# Generated by FakeRAM 2.0 (routing-friendly)
VERSION 5.7 ;
BUSBITCHARS "[]" ;
PROPERTYDEFINITIONS
  MACRO width INTEGER ;
  MACRO depth INTEGER ;
  MACRO banks INTEGER ;
END PROPERTYDEFINITIONS
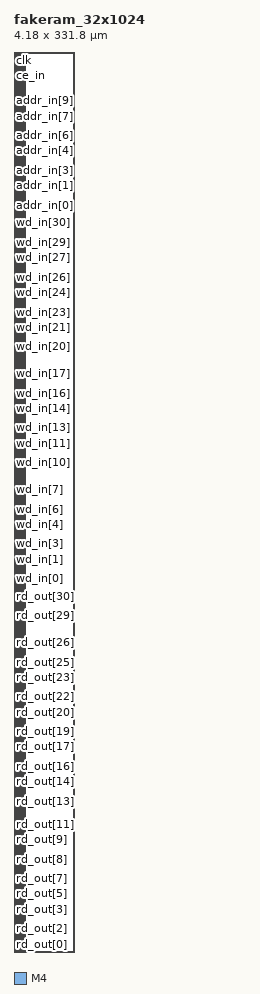
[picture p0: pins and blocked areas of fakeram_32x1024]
MACRO fakeram_32x1024
  PROPERTY width 32 ;
  PROPERTY depth 1024 ;
  PROPERTY banks 1 ;
  FOREIGN fakeram_32x1024 0 0 ;
  SYMMETRY X Y R90 ;
  SIZE 4.180 BY 331.800 ;
  CLASS BLOCK ;
  PIN rd_out[0]
    DIRECTION OUTPUT ;
    USE SIGNAL ;
    PORT
      LAYER M4 ;
      RECT 1.000 0.048 3.000 0.072 ;
    END
    PORT
      LAYER M4 ;
      RECT 1.000 0.036 4.000 0.084 ;
    END
  END rd_out[0]
  PIN rd_out[1]
    DIRECTION OUTPUT ;
    USE SIGNAL ;
    PORT
      LAYER M4 ;
      RECT 1.000 4.320 3.000 4.344 ;
    END
    PORT
      LAYER M4 ;
      RECT 1.000 4.308 4.000 4.356 ;
    END
  END rd_out[1]
  PIN rd_out[2]
    DIRECTION OUTPUT ;
    USE SIGNAL ;
    PORT
      LAYER M4 ;
      RECT 1.000 8.592 3.000 8.616 ;
    END
    PORT
      LAYER M4 ;
      RECT 1.000 8.580 4.000 8.628 ;
    END
  END rd_out[2]
  PIN rd_out[3]
    DIRECTION OUTPUT ;
    USE SIGNAL ;
    PORT
      LAYER M4 ;
      RECT 1.000 12.864 3.000 12.888 ;
    END
    PORT
      LAYER M4 ;
      RECT 1.000 12.852 4.000 12.900 ;
    END
  END rd_out[3]
  PIN rd_out[4]
    DIRECTION OUTPUT ;
    USE SIGNAL ;
    PORT
      LAYER M4 ;
      RECT 1.000 17.136 3.000 17.160 ;
    END
    PORT
      LAYER M4 ;
      RECT 1.000 17.124 4.000 17.172 ;
    END
  END rd_out[4]
  PIN rd_out[5]
    DIRECTION OUTPUT ;
    USE SIGNAL ;
    PORT
      LAYER M4 ;
      RECT 1.000 21.408 3.000 21.432 ;
    END
    PORT
      LAYER M4 ;
      RECT 1.000 21.396 4.000 21.444 ;
    END
  END rd_out[5]
  PIN rd_out[6]
    DIRECTION OUTPUT ;
    USE SIGNAL ;
    PORT
      LAYER M4 ;
      RECT 1.000 25.680 3.000 25.704 ;
    END
    PORT
      LAYER M4 ;
      RECT 1.000 25.668 4.000 25.716 ;
    END
  END rd_out[6]
  PIN rd_out[7]
    DIRECTION OUTPUT ;
    USE SIGNAL ;
    PORT
      LAYER M4 ;
      RECT 1.000 29.952 3.000 29.976 ;
    END
    PORT
      LAYER M4 ;
      RECT 1.000 29.940 4.000 29.988 ;
    END
  END rd_out[7]
  PIN rd_out[8]
    DIRECTION OUTPUT ;
    USE SIGNAL ;
    PORT
      LAYER M4 ;
      RECT 1.000 34.224 3.000 34.248 ;
    END
    PORT
      LAYER M4 ;
      RECT 1.000 34.212 4.000 34.260 ;
    END
  END rd_out[8]
  PIN rd_out[9]
    DIRECTION OUTPUT ;
    USE SIGNAL ;
    PORT
      LAYER M4 ;
      RECT 1.000 38.496 3.000 38.520 ;
    END
    PORT
      LAYER M4 ;
      RECT 1.000 38.484 4.000 38.532 ;
    END
  END rd_out[9]
  PIN rd_out[10]
    DIRECTION OUTPUT ;
    USE SIGNAL ;
    PORT
      LAYER M4 ;
      RECT 1.000 42.768 3.000 42.792 ;
    END
    PORT
      LAYER M4 ;
      RECT 1.000 42.756 4.000 42.804 ;
    END
  END rd_out[10]
  PIN rd_out[11]
    DIRECTION OUTPUT ;
    USE SIGNAL ;
    PORT
      LAYER M4 ;
      RECT 1.000 47.040 3.000 47.064 ;
    END
    PORT
      LAYER M4 ;
      RECT 1.000 47.028 4.000 47.076 ;
    END
  END rd_out[11]
  PIN rd_out[12]
    DIRECTION OUTPUT ;
    USE SIGNAL ;
    PORT
      LAYER M4 ;
      RECT 1.000 51.312 3.000 51.336 ;
    END
    PORT
      LAYER M4 ;
      RECT 1.000 51.300 4.000 51.348 ;
    END
  END rd_out[12]
  PIN rd_out[13]
    DIRECTION OUTPUT ;
    USE SIGNAL ;
    PORT
      LAYER M4 ;
      RECT 1.000 55.584 3.000 55.608 ;
    END
    PORT
      LAYER M4 ;
      RECT 1.000 55.572 4.000 55.620 ;
    END
  END rd_out[13]
  PIN rd_out[14]
    DIRECTION OUTPUT ;
    USE SIGNAL ;
    PORT
      LAYER M4 ;
      RECT 1.000 59.856 3.000 59.880 ;
    END
    PORT
      LAYER M4 ;
      RECT 1.000 59.844 4.000 59.892 ;
    END
  END rd_out[14]
  PIN rd_out[15]
    DIRECTION OUTPUT ;
    USE SIGNAL ;
    PORT
      LAYER M4 ;
      RECT 1.000 64.128 3.000 64.152 ;
    END
    PORT
      LAYER M4 ;
      RECT 1.000 64.116 4.000 64.164 ;
    END
  END rd_out[15]
  PIN rd_out[16]
    DIRECTION OUTPUT ;
    USE SIGNAL ;
    PORT
      LAYER M4 ;
      RECT 1.000 68.400 3.000 68.424 ;
    END
    PORT
      LAYER M4 ;
      RECT 1.000 68.388 4.000 68.436 ;
    END
  END rd_out[16]
  PIN rd_out[17]
    DIRECTION OUTPUT ;
    USE SIGNAL ;
    PORT
      LAYER M4 ;
      RECT 1.000 72.672 3.000 72.696 ;
    END
    PORT
      LAYER M4 ;
      RECT 1.000 72.660 4.000 72.708 ;
    END
  END rd_out[17]
  PIN rd_out[18]
    DIRECTION OUTPUT ;
    USE SIGNAL ;
    PORT
      LAYER M4 ;
      RECT 1.000 76.944 3.000 76.968 ;
    END
    PORT
      LAYER M4 ;
      RECT 1.000 76.932 4.000 76.980 ;
    END
  END rd_out[18]
  PIN rd_out[19]
    DIRECTION OUTPUT ;
    USE SIGNAL ;
    PORT
      LAYER M4 ;
      RECT 1.000 81.216 3.000 81.240 ;
    END
    PORT
      LAYER M4 ;
      RECT 1.000 81.204 4.000 81.252 ;
    END
  END rd_out[19]
  PIN rd_out[20]
    DIRECTION OUTPUT ;
    USE SIGNAL ;
    PORT
      LAYER M4 ;
      RECT 1.000 85.488 3.000 85.512 ;
    END
    PORT
      LAYER M4 ;
      RECT 1.000 85.476 4.000 85.524 ;
    END
  END rd_out[20]
  PIN rd_out[21]
    DIRECTION OUTPUT ;
    USE SIGNAL ;
    PORT
      LAYER M4 ;
      RECT 1.000 89.760 3.000 89.784 ;
    END
    PORT
      LAYER M4 ;
      RECT 1.000 89.748 4.000 89.796 ;
    END
  END rd_out[21]
  PIN rd_out[22]
    DIRECTION OUTPUT ;
    USE SIGNAL ;
    PORT
      LAYER M4 ;
      RECT 1.000 94.032 3.000 94.056 ;
    END
    PORT
      LAYER M4 ;
      RECT 1.000 94.020 4.000 94.068 ;
    END
  END rd_out[22]
  PIN rd_out[23]
    DIRECTION OUTPUT ;
    USE SIGNAL ;
    PORT
      LAYER M4 ;
      RECT 1.000 98.304 3.000 98.328 ;
    END
    PORT
      LAYER M4 ;
      RECT 1.000 98.292 4.000 98.340 ;
    END
  END rd_out[23]
  PIN rd_out[24]
    DIRECTION OUTPUT ;
    USE SIGNAL ;
    PORT
      LAYER M4 ;
      RECT 1.000 102.576 3.000 102.600 ;
    END
    PORT
      LAYER M4 ;
      RECT 1.000 102.564 4.000 102.612 ;
    END
  END rd_out[24]
  PIN rd_out[25]
    DIRECTION OUTPUT ;
    USE SIGNAL ;
    PORT
      LAYER M4 ;
      RECT 1.000 106.848 3.000 106.872 ;
    END
    PORT
      LAYER M4 ;
      RECT 1.000 106.836 4.000 106.884 ;
    END
  END rd_out[25]
  PIN rd_out[26]
    DIRECTION OUTPUT ;
    USE SIGNAL ;
    PORT
      LAYER M4 ;
      RECT 1.000 111.120 3.000 111.144 ;
    END
    PORT
      LAYER M4 ;
      RECT 1.000 111.108 4.000 111.156 ;
    END
  END rd_out[26]
  PIN rd_out[27]
    DIRECTION OUTPUT ;
    USE SIGNAL ;
    PORT
      LAYER M4 ;
      RECT 1.000 115.392 3.000 115.416 ;
    END
    PORT
      LAYER M4 ;
      RECT 1.000 115.380 4.000 115.428 ;
    END
  END rd_out[27]
  PIN rd_out[28]
    DIRECTION OUTPUT ;
    USE SIGNAL ;
    PORT
      LAYER M4 ;
      RECT 1.000 119.664 3.000 119.688 ;
    END
    PORT
      LAYER M4 ;
      RECT 1.000 119.652 4.000 119.700 ;
    END
  END rd_out[28]
  PIN rd_out[29]
    DIRECTION OUTPUT ;
    USE SIGNAL ;
    PORT
      LAYER M4 ;
      RECT 1.000 123.936 3.000 123.960 ;
    END
    PORT
      LAYER M4 ;
      RECT 1.000 123.924 4.000 123.972 ;
    END
  END rd_out[29]
  PIN rd_out[30]
    DIRECTION OUTPUT ;
    USE SIGNAL ;
    PORT
      LAYER M4 ;
      RECT 1.000 128.208 3.000 128.232 ;
    END
    PORT
      LAYER M4 ;
      RECT 1.000 128.196 4.000 128.244 ;
    END
  END rd_out[30]
  PIN rd_out[31]
    DIRECTION OUTPUT ;
    USE SIGNAL ;
    PORT
      LAYER M4 ;
      RECT 1.000 132.480 3.000 132.504 ;
    END
    PORT
      LAYER M4 ;
      RECT 1.000 132.468 4.000 132.516 ;
    END
  END rd_out[31]
  PIN wd_in[0]
    DIRECTION INPUT ;
    USE SIGNAL ;
    PORT
      LAYER M4 ;
      RECT 1.000 137.664 3.000 137.688 ;
    END
    PORT
      LAYER M4 ;
      RECT 1.000 137.652 4.000 137.700 ;
    END
  END wd_in[0]
  PIN wd_in[1]
    DIRECTION INPUT ;
    USE SIGNAL ;
    PORT
      LAYER M4 ;
      RECT 1.000 141.936 3.000 141.960 ;
    END
    PORT
      LAYER M4 ;
      RECT 1.000 141.924 4.000 141.972 ;
    END
  END wd_in[1]
  PIN wd_in[2]
    DIRECTION INPUT ;
    USE SIGNAL ;
    PORT
      LAYER M4 ;
      RECT 1.000 146.208 3.000 146.232 ;
    END
    PORT
      LAYER M4 ;
      RECT 1.000 146.196 4.000 146.244 ;
    END
  END wd_in[2]
  PIN wd_in[3]
    DIRECTION INPUT ;
    USE SIGNAL ;
    PORT
      LAYER M4 ;
      RECT 1.000 150.480 3.000 150.504 ;
    END
    PORT
      LAYER M4 ;
      RECT 1.000 150.468 4.000 150.516 ;
    END
  END wd_in[3]
  PIN wd_in[4]
    DIRECTION INPUT ;
    USE SIGNAL ;
    PORT
      LAYER M4 ;
      RECT 1.000 154.752 3.000 154.776 ;
    END
    PORT
      LAYER M4 ;
      RECT 1.000 154.740 4.000 154.788 ;
    END
  END wd_in[4]
  PIN wd_in[5]
    DIRECTION INPUT ;
    USE SIGNAL ;
    PORT
      LAYER M4 ;
      RECT 1.000 159.024 3.000 159.048 ;
    END
    PORT
      LAYER M4 ;
      RECT 1.000 159.012 4.000 159.060 ;
    END
  END wd_in[5]
  PIN wd_in[6]
    DIRECTION INPUT ;
    USE SIGNAL ;
    PORT
      LAYER M4 ;
      RECT 1.000 163.296 3.000 163.320 ;
    END
    PORT
      LAYER M4 ;
      RECT 1.000 163.284 4.000 163.332 ;
    END
  END wd_in[6]
  PIN wd_in[7]
    DIRECTION INPUT ;
    USE SIGNAL ;
    PORT
      LAYER M4 ;
      RECT 1.000 167.568 3.000 167.592 ;
    END
    PORT
      LAYER M4 ;
      RECT 1.000 167.556 4.000 167.604 ;
    END
  END wd_in[7]
  PIN wd_in[8]
    DIRECTION INPUT ;
    USE SIGNAL ;
    PORT
      LAYER M4 ;
      RECT 1.000 171.840 3.000 171.864 ;
    END
    PORT
      LAYER M4 ;
      RECT 1.000 171.828 4.000 171.876 ;
    END
  END wd_in[8]
  PIN wd_in[9]
    DIRECTION INPUT ;
    USE SIGNAL ;
    PORT
      LAYER M4 ;
      RECT 1.000 176.112 3.000 176.136 ;
    END
    PORT
      LAYER M4 ;
      RECT 1.000 176.100 4.000 176.148 ;
    END
  END wd_in[9]
  PIN wd_in[10]
    DIRECTION INPUT ;
    USE SIGNAL ;
    PORT
      LAYER M4 ;
      RECT 1.000 180.384 3.000 180.408 ;
    END
    PORT
      LAYER M4 ;
      RECT 1.000 180.372 4.000 180.420 ;
    END
  END wd_in[10]
  PIN wd_in[11]
    DIRECTION INPUT ;
    USE SIGNAL ;
    PORT
      LAYER M4 ;
      RECT 1.000 184.656 3.000 184.680 ;
    END
    PORT
      LAYER M4 ;
      RECT 1.000 184.644 4.000 184.692 ;
    END
  END wd_in[11]
  PIN wd_in[12]
    DIRECTION INPUT ;
    USE SIGNAL ;
    PORT
      LAYER M4 ;
      RECT 1.000 188.928 3.000 188.952 ;
    END
    PORT
      LAYER M4 ;
      RECT 1.000 188.916 4.000 188.964 ;
    END
  END wd_in[12]
  PIN wd_in[13]
    DIRECTION INPUT ;
    USE SIGNAL ;
    PORT
      LAYER M4 ;
      RECT 1.000 193.200 3.000 193.224 ;
    END
    PORT
      LAYER M4 ;
      RECT 1.000 193.188 4.000 193.236 ;
    END
  END wd_in[13]
  PIN wd_in[14]
    DIRECTION INPUT ;
    USE SIGNAL ;
    PORT
      LAYER M4 ;
      RECT 1.000 197.472 3.000 197.496 ;
    END
    PORT
      LAYER M4 ;
      RECT 1.000 197.460 4.000 197.508 ;
    END
  END wd_in[14]
  PIN wd_in[15]
    DIRECTION INPUT ;
    USE SIGNAL ;
    PORT
      LAYER M4 ;
      RECT 1.000 201.744 3.000 201.768 ;
    END
    PORT
      LAYER M4 ;
      RECT 1.000 201.732 4.000 201.780 ;
    END
  END wd_in[15]
  PIN wd_in[16]
    DIRECTION INPUT ;
    USE SIGNAL ;
    PORT
      LAYER M4 ;
      RECT 1.000 206.016 3.000 206.040 ;
    END
    PORT
      LAYER M4 ;
      RECT 1.000 206.004 4.000 206.052 ;
    END
  END wd_in[16]
  PIN wd_in[17]
    DIRECTION INPUT ;
    USE SIGNAL ;
    PORT
      LAYER M4 ;
      RECT 1.000 210.288 3.000 210.312 ;
    END
    PORT
      LAYER M4 ;
      RECT 1.000 210.276 4.000 210.324 ;
    END
  END wd_in[17]
  PIN wd_in[18]
    DIRECTION INPUT ;
    USE SIGNAL ;
    PORT
      LAYER M4 ;
      RECT 1.000 214.560 3.000 214.584 ;
    END
    PORT
      LAYER M4 ;
      RECT 1.000 214.548 4.000 214.596 ;
    END
  END wd_in[18]
  PIN wd_in[19]
    DIRECTION INPUT ;
    USE SIGNAL ;
    PORT
      LAYER M4 ;
      RECT 1.000 218.832 3.000 218.856 ;
    END
    PORT
      LAYER M4 ;
      RECT 1.000 218.820 4.000 218.868 ;
    END
  END wd_in[19]
  PIN wd_in[20]
    DIRECTION INPUT ;
    USE SIGNAL ;
    PORT
      LAYER M4 ;
      RECT 1.000 223.104 3.000 223.128 ;
    END
    PORT
      LAYER M4 ;
      RECT 1.000 223.092 4.000 223.140 ;
    END
  END wd_in[20]
  PIN wd_in[21]
    DIRECTION INPUT ;
    USE SIGNAL ;
    PORT
      LAYER M4 ;
      RECT 1.000 227.376 3.000 227.400 ;
    END
    PORT
      LAYER M4 ;
      RECT 1.000 227.364 4.000 227.412 ;
    END
  END wd_in[21]
  PIN wd_in[22]
    DIRECTION INPUT ;
    USE SIGNAL ;
    PORT
      LAYER M4 ;
      RECT 1.000 231.648 3.000 231.672 ;
    END
    PORT
      LAYER M4 ;
      RECT 1.000 231.636 4.000 231.684 ;
    END
  END wd_in[22]
  PIN wd_in[23]
    DIRECTION INPUT ;
    USE SIGNAL ;
    PORT
      LAYER M4 ;
      RECT 1.000 235.920 3.000 235.944 ;
    END
    PORT
      LAYER M4 ;
      RECT 1.000 235.908 4.000 235.956 ;
    END
  END wd_in[23]
  PIN wd_in[24]
    DIRECTION INPUT ;
    USE SIGNAL ;
    PORT
      LAYER M4 ;
      RECT 1.000 240.192 3.000 240.216 ;
    END
    PORT
      LAYER M4 ;
      RECT 1.000 240.180 4.000 240.228 ;
    END
  END wd_in[24]
  PIN wd_in[25]
    DIRECTION INPUT ;
    USE SIGNAL ;
    PORT
      LAYER M4 ;
      RECT 1.000 244.464 3.000 244.488 ;
    END
    PORT
      LAYER M4 ;
      RECT 1.000 244.452 4.000 244.500 ;
    END
  END wd_in[25]
  PIN wd_in[26]
    DIRECTION INPUT ;
    USE SIGNAL ;
    PORT
      LAYER M4 ;
      RECT 1.000 248.736 3.000 248.760 ;
    END
    PORT
      LAYER M4 ;
      RECT 1.000 248.724 4.000 248.772 ;
    END
  END wd_in[26]
  PIN wd_in[27]
    DIRECTION INPUT ;
    USE SIGNAL ;
    PORT
      LAYER M4 ;
      RECT 1.000 253.008 3.000 253.032 ;
    END
    PORT
      LAYER M4 ;
      RECT 1.000 252.996 4.000 253.044 ;
    END
  END wd_in[27]
  PIN wd_in[28]
    DIRECTION INPUT ;
    USE SIGNAL ;
    PORT
      LAYER M4 ;
      RECT 1.000 257.280 3.000 257.304 ;
    END
    PORT
      LAYER M4 ;
      RECT 1.000 257.268 4.000 257.316 ;
    END
  END wd_in[28]
  PIN wd_in[29]
    DIRECTION INPUT ;
    USE SIGNAL ;
    PORT
      LAYER M4 ;
      RECT 1.000 261.552 3.000 261.576 ;
    END
    PORT
      LAYER M4 ;
      RECT 1.000 261.540 4.000 261.588 ;
    END
  END wd_in[29]
  PIN wd_in[30]
    DIRECTION INPUT ;
    USE SIGNAL ;
    PORT
      LAYER M4 ;
      RECT 1.000 265.824 3.000 265.848 ;
    END
    PORT
      LAYER M4 ;
      RECT 1.000 265.812 4.000 265.860 ;
    END
  END wd_in[30]
  PIN wd_in[31]
    DIRECTION INPUT ;
    USE SIGNAL ;
    PORT
      LAYER M4 ;
      RECT 1.000 270.096 3.000 270.120 ;
    END
    PORT
      LAYER M4 ;
      RECT 1.000 270.084 4.000 270.132 ;
    END
  END wd_in[31]
  PIN addr_in[0]
    DIRECTION INPUT ;
    USE SIGNAL ;
    PORT
      LAYER M4 ;
      RECT 1.000 275.280 3.000 275.304 ;
    END
    PORT
      LAYER M4 ;
      RECT 1.000 275.268 4.000 275.316 ;
    END
  END addr_in[0]
  PIN addr_in[1]
    DIRECTION INPUT ;
    USE SIGNAL ;
    PORT
      LAYER M4 ;
      RECT 1.000 279.552 3.000 279.576 ;
    END
    PORT
      LAYER M4 ;
      RECT 1.000 279.540 4.000 279.588 ;
    END
  END addr_in[1]
  PIN addr_in[2]
    DIRECTION INPUT ;
    USE SIGNAL ;
    PORT
      LAYER M4 ;
      RECT 1.000 283.824 3.000 283.848 ;
    END
    PORT
      LAYER M4 ;
      RECT 1.000 283.812 4.000 283.860 ;
    END
  END addr_in[2]
  PIN addr_in[3]
    DIRECTION INPUT ;
    USE SIGNAL ;
    PORT
      LAYER M4 ;
      RECT 1.000 288.096 3.000 288.120 ;
    END
    PORT
      LAYER M4 ;
      RECT 1.000 288.084 4.000 288.132 ;
    END
  END addr_in[3]
  PIN addr_in[4]
    DIRECTION INPUT ;
    USE SIGNAL ;
    PORT
      LAYER M4 ;
      RECT 1.000 292.368 3.000 292.392 ;
    END
    PORT
      LAYER M4 ;
      RECT 1.000 292.356 4.000 292.404 ;
    END
  END addr_in[4]
  PIN addr_in[5]
    DIRECTION INPUT ;
    USE SIGNAL ;
    PORT
      LAYER M4 ;
      RECT 1.000 296.640 3.000 296.664 ;
    END
    PORT
      LAYER M4 ;
      RECT 1.000 296.628 4.000 296.676 ;
    END
  END addr_in[5]
  PIN addr_in[6]
    DIRECTION INPUT ;
    USE SIGNAL ;
    PORT
      LAYER M4 ;
      RECT 1.000 300.912 3.000 300.936 ;
    END
    PORT
      LAYER M4 ;
      RECT 1.000 300.900 4.000 300.948 ;
    END
  END addr_in[6]
  PIN addr_in[7]
    DIRECTION INPUT ;
    USE SIGNAL ;
    PORT
      LAYER M4 ;
      RECT 1.000 305.184 3.000 305.208 ;
    END
    PORT
      LAYER M4 ;
      RECT 1.000 305.172 4.000 305.220 ;
    END
  END addr_in[7]
  PIN addr_in[8]
    DIRECTION INPUT ;
    USE SIGNAL ;
    PORT
      LAYER M4 ;
      RECT 1.000 309.456 3.000 309.480 ;
    END
    PORT
      LAYER M4 ;
      RECT 1.000 309.444 4.000 309.492 ;
    END
  END addr_in[8]
  PIN addr_in[9]
    DIRECTION INPUT ;
    USE SIGNAL ;
    PORT
      LAYER M4 ;
      RECT 1.000 313.728 3.000 313.752 ;
    END
    PORT
      LAYER M4 ;
      RECT 1.000 313.716 4.000 313.764 ;
    END
  END addr_in[9]
  PIN we_in
    DIRECTION INPUT ;
    USE SIGNAL ;
    PORT
      LAYER M4 ;
      RECT 1.000 318.912 3.000 318.936 ;
    END
    PORT
      LAYER M4 ;
      RECT 1.000 318.900 4.000 318.948 ;
    END
  END we_in
  PIN ce_in
    DIRECTION INPUT ;
    USE SIGNAL ;
    PORT
      LAYER M4 ;
      RECT 1.000 323.184 3.000 323.208 ;
    END
    PORT
      LAYER M4 ;
      RECT 1.000 323.172 4.000 323.220 ;
    END
  END ce_in
  PIN clk
    DIRECTION INPUT ;
    USE SIGNAL ;
    PORT
      LAYER M4 ;
      RECT 1.000 327.456 3.000 327.480 ;
    END
    PORT
      LAYER M4 ;
      RECT 1.000 327.444 4.000 327.492 ;
    END
  END clk
  PIN VSS
    DIRECTION INOUT ;
    USE GROUND ;
    PORT
      LAYER M4 ;
      RECT 0.048 0.000 4.132 0.096 ;
      RECT 0.048 0.768 4.132 0.864 ;
      RECT 0.048 1.536 4.132 1.632 ;
      RECT 0.048 2.304 4.132 2.400 ;
      RECT 0.048 3.072 4.132 3.168 ;
      RECT 0.048 3.840 4.132 3.936 ;
      RECT 0.048 4.608 4.132 4.704 ;
      RECT 0.048 5.376 4.132 5.472 ;
      RECT 0.048 6.144 4.132 6.240 ;
      RECT 0.048 6.912 4.132 7.008 ;
      RECT 0.048 7.680 4.132 7.776 ;
      RECT 0.048 8.448 4.132 8.544 ;
      RECT 0.048 9.216 4.132 9.312 ;
      RECT 0.048 9.984 4.132 10.080 ;
      RECT 0.048 10.752 4.132 10.848 ;
      RECT 0.048 11.520 4.132 11.616 ;
      RECT 0.048 12.288 4.132 12.384 ;
      RECT 0.048 13.056 4.132 13.152 ;
      RECT 0.048 13.824 4.132 13.920 ;
      RECT 0.048 14.592 4.132 14.688 ;
      RECT 0.048 15.360 4.132 15.456 ;
      RECT 0.048 16.128 4.132 16.224 ;
      RECT 0.048 16.896 4.132 16.992 ;
      RECT 0.048 17.664 4.132 17.760 ;
      RECT 0.048 18.432 4.132 18.528 ;
      RECT 0.048 19.200 4.132 19.296 ;
      RECT 0.048 19.968 4.132 20.064 ;
      RECT 0.048 20.736 4.132 20.832 ;
      RECT 0.048 21.504 4.132 21.600 ;
      RECT 0.048 22.272 4.132 22.368 ;
      RECT 0.048 23.040 4.132 23.136 ;
      RECT 0.048 23.808 4.132 23.904 ;
      RECT 0.048 24.576 4.132 24.672 ;
      RECT 0.048 25.344 4.132 25.440 ;
      RECT 0.048 26.112 4.132 26.208 ;
      RECT 0.048 26.880 4.132 26.976 ;
      RECT 0.048 27.648 4.132 27.744 ;
      RECT 0.048 28.416 4.132 28.512 ;
      RECT 0.048 29.184 4.132 29.280 ;
      RECT 0.048 29.952 4.132 30.048 ;
      RECT 0.048 30.720 4.132 30.816 ;
      RECT 0.048 31.488 4.132 31.584 ;
      RECT 0.048 32.256 4.132 32.352 ;
      RECT 0.048 33.024 4.132 33.120 ;
      RECT 0.048 33.792 4.132 33.888 ;
      RECT 0.048 34.560 4.132 34.656 ;
      RECT 0.048 35.328 4.132 35.424 ;
      RECT 0.048 36.096 4.132 36.192 ;
      RECT 0.048 36.864 4.132 36.960 ;
      RECT 0.048 37.632 4.132 37.728 ;
      RECT 0.048 38.400 4.132 38.496 ;
      RECT 0.048 39.168 4.132 39.264 ;
      RECT 0.048 39.936 4.132 40.032 ;
      RECT 0.048 40.704 4.132 40.800 ;
      RECT 0.048 41.472 4.132 41.568 ;
      RECT 0.048 42.240 4.132 42.336 ;
      RECT 0.048 43.008 4.132 43.104 ;
      RECT 0.048 43.776 4.132 43.872 ;
      RECT 0.048 44.544 4.132 44.640 ;
      RECT 0.048 45.312 4.132 45.408 ;
      RECT 0.048 46.080 4.132 46.176 ;
      RECT 0.048 46.848 4.132 46.944 ;
      RECT 0.048 47.616 4.132 47.712 ;
      RECT 0.048 48.384 4.132 48.480 ;
      RECT 0.048 49.152 4.132 49.248 ;
      RECT 0.048 49.920 4.132 50.016 ;
      RECT 0.048 50.688 4.132 50.784 ;
      RECT 0.048 51.456 4.132 51.552 ;
      RECT 0.048 52.224 4.132 52.320 ;
      RECT 0.048 52.992 4.132 53.088 ;
      RECT 0.048 53.760 4.132 53.856 ;
      RECT 0.048 54.528 4.132 54.624 ;
      RECT 0.048 55.296 4.132 55.392 ;
      RECT 0.048 56.064 4.132 56.160 ;
      RECT 0.048 56.832 4.132 56.928 ;
      RECT 0.048 57.600 4.132 57.696 ;
      RECT 0.048 58.368 4.132 58.464 ;
      RECT 0.048 59.136 4.132 59.232 ;
      RECT 0.048 59.904 4.132 60.000 ;
      RECT 0.048 60.672 4.132 60.768 ;
      RECT 0.048 61.440 4.132 61.536 ;
      RECT 0.048 62.208 4.132 62.304 ;
      RECT 0.048 62.976 4.132 63.072 ;
      RECT 0.048 63.744 4.132 63.840 ;
      RECT 0.048 64.512 4.132 64.608 ;
      RECT 0.048 65.280 4.132 65.376 ;
      RECT 0.048 66.048 4.132 66.144 ;
      RECT 0.048 66.816 4.132 66.912 ;
      RECT 0.048 67.584 4.132 67.680 ;
      RECT 0.048 68.352 4.132 68.448 ;
      RECT 0.048 69.120 4.132 69.216 ;
      RECT 0.048 69.888 4.132 69.984 ;
      RECT 0.048 70.656 4.132 70.752 ;
      RECT 0.048 71.424 4.132 71.520 ;
      RECT 0.048 72.192 4.132 72.288 ;
      RECT 0.048 72.960 4.132 73.056 ;
      RECT 0.048 73.728 4.132 73.824 ;
      RECT 0.048 74.496 4.132 74.592 ;
      RECT 0.048 75.264 4.132 75.360 ;
      RECT 0.048 76.032 4.132 76.128 ;
      RECT 0.048 76.800 4.132 76.896 ;
      RECT 0.048 77.568 4.132 77.664 ;
      RECT 0.048 78.336 4.132 78.432 ;
      RECT 0.048 79.104 4.132 79.200 ;
      RECT 0.048 79.872 4.132 79.968 ;
      RECT 0.048 80.640 4.132 80.736 ;
      RECT 0.048 81.408 4.132 81.504 ;
      RECT 0.048 82.176 4.132 82.272 ;
      RECT 0.048 82.944 4.132 83.040 ;
      RECT 0.048 83.712 4.132 83.808 ;
      RECT 0.048 84.480 4.132 84.576 ;
      RECT 0.048 85.248 4.132 85.344 ;
      RECT 0.048 86.016 4.132 86.112 ;
      RECT 0.048 86.784 4.132 86.880 ;
      RECT 0.048 87.552 4.132 87.648 ;
      RECT 0.048 88.320 4.132 88.416 ;
      RECT 0.048 89.088 4.132 89.184 ;
      RECT 0.048 89.856 4.132 89.952 ;
      RECT 0.048 90.624 4.132 90.720 ;
      RECT 0.048 91.392 4.132 91.488 ;
      RECT 0.048 92.160 4.132 92.256 ;
      RECT 0.048 92.928 4.132 93.024 ;
      RECT 0.048 93.696 4.132 93.792 ;
      RECT 0.048 94.464 4.132 94.560 ;
      RECT 0.048 95.232 4.132 95.328 ;
      RECT 0.048 96.000 4.132 96.096 ;
      RECT 0.048 96.768 4.132 96.864 ;
      RECT 0.048 97.536 4.132 97.632 ;
      RECT 0.048 98.304 4.132 98.400 ;
      RECT 0.048 99.072 4.132 99.168 ;
      RECT 0.048 99.840 4.132 99.936 ;
      RECT 0.048 100.608 4.132 100.704 ;
      RECT 0.048 101.376 4.132 101.472 ;
      RECT 0.048 102.144 4.132 102.240 ;
      RECT 0.048 102.912 4.132 103.008 ;
      RECT 0.048 103.680 4.132 103.776 ;
      RECT 0.048 104.448 4.132 104.544 ;
      RECT 0.048 105.216 4.132 105.312 ;
      RECT 0.048 105.984 4.132 106.080 ;
      RECT 0.048 106.752 4.132 106.848 ;
      RECT 0.048 107.520 4.132 107.616 ;
      RECT 0.048 108.288 4.132 108.384 ;
      RECT 0.048 109.056 4.132 109.152 ;
      RECT 0.048 109.824 4.132 109.920 ;
      RECT 0.048 110.592 4.132 110.688 ;
      RECT 0.048 111.360 4.132 111.456 ;
      RECT 0.048 112.128 4.132 112.224 ;
      RECT 0.048 112.896 4.132 112.992 ;
      RECT 0.048 113.664 4.132 113.760 ;
      RECT 0.048 114.432 4.132 114.528 ;
      RECT 0.048 115.200 4.132 115.296 ;
      RECT 0.048 115.968 4.132 116.064 ;
      RECT 0.048 116.736 4.132 116.832 ;
      RECT 0.048 117.504 4.132 117.600 ;
      RECT 0.048 118.272 4.132 118.368 ;
      RECT 0.048 119.040 4.132 119.136 ;
      RECT 0.048 119.808 4.132 119.904 ;
      RECT 0.048 120.576 4.132 120.672 ;
      RECT 0.048 121.344 4.132 121.440 ;
      RECT 0.048 122.112 4.132 122.208 ;
      RECT 0.048 122.880 4.132 122.976 ;
      RECT 0.048 123.648 4.132 123.744 ;
      RECT 0.048 124.416 4.132 124.512 ;
      RECT 0.048 125.184 4.132 125.280 ;
      RECT 0.048 125.952 4.132 126.048 ;
      RECT 0.048 126.720 4.132 126.816 ;
      RECT 0.048 127.488 4.132 127.584 ;
      RECT 0.048 128.256 4.132 128.352 ;
      RECT 0.048 129.024 4.132 129.120 ;
      RECT 0.048 129.792 4.132 129.888 ;
      RECT 0.048 130.560 4.132 130.656 ;
      RECT 0.048 131.328 4.132 131.424 ;
      RECT 0.048 132.096 4.132 132.192 ;
      RECT 0.048 132.864 4.132 132.960 ;
      RECT 0.048 133.632 4.132 133.728 ;
      RECT 0.048 134.400 4.132 134.496 ;
      RECT 0.048 135.168 4.132 135.264 ;
      RECT 0.048 135.936 4.132 136.032 ;
      RECT 0.048 136.704 4.132 136.800 ;
      RECT 0.048 137.472 4.132 137.568 ;
      RECT 0.048 138.240 4.132 138.336 ;
      RECT 0.048 139.008 4.132 139.104 ;
      RECT 0.048 139.776 4.132 139.872 ;
      RECT 0.048 140.544 4.132 140.640 ;
      RECT 0.048 141.312 4.132 141.408 ;
      RECT 0.048 142.080 4.132 142.176 ;
      RECT 0.048 142.848 4.132 142.944 ;
      RECT 0.048 143.616 4.132 143.712 ;
      RECT 0.048 144.384 4.132 144.480 ;
      RECT 0.048 145.152 4.132 145.248 ;
      RECT 0.048 145.920 4.132 146.016 ;
      RECT 0.048 146.688 4.132 146.784 ;
      RECT 0.048 147.456 4.132 147.552 ;
      RECT 0.048 148.224 4.132 148.320 ;
      RECT 0.048 148.992 4.132 149.088 ;
      RECT 0.048 149.760 4.132 149.856 ;
      RECT 0.048 150.528 4.132 150.624 ;
      RECT 0.048 151.296 4.132 151.392 ;
      RECT 0.048 152.064 4.132 152.160 ;
      RECT 0.048 152.832 4.132 152.928 ;
      RECT 0.048 153.600 4.132 153.696 ;
      RECT 0.048 154.368 4.132 154.464 ;
      RECT 0.048 155.136 4.132 155.232 ;
      RECT 0.048 155.904 4.132 156.000 ;
      RECT 0.048 156.672 4.132 156.768 ;
      RECT 0.048 157.440 4.132 157.536 ;
      RECT 0.048 158.208 4.132 158.304 ;
      RECT 0.048 158.976 4.132 159.072 ;
      RECT 0.048 159.744 4.132 159.840 ;
      RECT 0.048 160.512 4.132 160.608 ;
      RECT 0.048 161.280 4.132 161.376 ;
      RECT 0.048 162.048 4.132 162.144 ;
      RECT 0.048 162.816 4.132 162.912 ;
      RECT 0.048 163.584 4.132 163.680 ;
      RECT 0.048 164.352 4.132 164.448 ;
      RECT 0.048 165.120 4.132 165.216 ;
      RECT 0.048 165.888 4.132 165.984 ;
      RECT 0.048 166.656 4.132 166.752 ;
      RECT 0.048 167.424 4.132 167.520 ;
      RECT 0.048 168.192 4.132 168.288 ;
      RECT 0.048 168.960 4.132 169.056 ;
      RECT 0.048 169.728 4.132 169.824 ;
      RECT 0.048 170.496 4.132 170.592 ;
      RECT 0.048 171.264 4.132 171.360 ;
      RECT 0.048 172.032 4.132 172.128 ;
      RECT 0.048 172.800 4.132 172.896 ;
      RECT 0.048 173.568 4.132 173.664 ;
      RECT 0.048 174.336 4.132 174.432 ;
      RECT 0.048 175.104 4.132 175.200 ;
      RECT 0.048 175.872 4.132 175.968 ;
      RECT 0.048 176.640 4.132 176.736 ;
      RECT 0.048 177.408 4.132 177.504 ;
      RECT 0.048 178.176 4.132 178.272 ;
      RECT 0.048 178.944 4.132 179.040 ;
      RECT 0.048 179.712 4.132 179.808 ;
      RECT 0.048 180.480 4.132 180.576 ;
      RECT 0.048 181.248 4.132 181.344 ;
      RECT 0.048 182.016 4.132 182.112 ;
      RECT 0.048 182.784 4.132 182.880 ;
      RECT 0.048 183.552 4.132 183.648 ;
      RECT 0.048 184.320 4.132 184.416 ;
      RECT 0.048 185.088 4.132 185.184 ;
      RECT 0.048 185.856 4.132 185.952 ;
      RECT 0.048 186.624 4.132 186.720 ;
      RECT 0.048 187.392 4.132 187.488 ;
      RECT 0.048 188.160 4.132 188.256 ;
      RECT 0.048 188.928 4.132 189.024 ;
      RECT 0.048 189.696 4.132 189.792 ;
      RECT 0.048 190.464 4.132 190.560 ;
      RECT 0.048 191.232 4.132 191.328 ;
      RECT 0.048 192.000 4.132 192.096 ;
      RECT 0.048 192.768 4.132 192.864 ;
      RECT 0.048 193.536 4.132 193.632 ;
      RECT 0.048 194.304 4.132 194.400 ;
      RECT 0.048 195.072 4.132 195.168 ;
      RECT 0.048 195.840 4.132 195.936 ;
      RECT 0.048 196.608 4.132 196.704 ;
      RECT 0.048 197.376 4.132 197.472 ;
      RECT 0.048 198.144 4.132 198.240 ;
      RECT 0.048 198.912 4.132 199.008 ;
      RECT 0.048 199.680 4.132 199.776 ;
      RECT 0.048 200.448 4.132 200.544 ;
      RECT 0.048 201.216 4.132 201.312 ;
      RECT 0.048 201.984 4.132 202.080 ;
      RECT 0.048 202.752 4.132 202.848 ;
      RECT 0.048 203.520 4.132 203.616 ;
      RECT 0.048 204.288 4.132 204.384 ;
      RECT 0.048 205.056 4.132 205.152 ;
      RECT 0.048 205.824 4.132 205.920 ;
      RECT 0.048 206.592 4.132 206.688 ;
      RECT 0.048 207.360 4.132 207.456 ;
      RECT 0.048 208.128 4.132 208.224 ;
      RECT 0.048 208.896 4.132 208.992 ;
      RECT 0.048 209.664 4.132 209.760 ;
      RECT 0.048 210.432 4.132 210.528 ;
      RECT 0.048 211.200 4.132 211.296 ;
      RECT 0.048 211.968 4.132 212.064 ;
      RECT 0.048 212.736 4.132 212.832 ;
      RECT 0.048 213.504 4.132 213.600 ;
      RECT 0.048 214.272 4.132 214.368 ;
      RECT 0.048 215.040 4.132 215.136 ;
      RECT 0.048 215.808 4.132 215.904 ;
      RECT 0.048 216.576 4.132 216.672 ;
      RECT 0.048 217.344 4.132 217.440 ;
      RECT 0.048 218.112 4.132 218.208 ;
      RECT 0.048 218.880 4.132 218.976 ;
      RECT 0.048 219.648 4.132 219.744 ;
      RECT 0.048 220.416 4.132 220.512 ;
      RECT 0.048 221.184 4.132 221.280 ;
      RECT 0.048 221.952 4.132 222.048 ;
      RECT 0.048 222.720 4.132 222.816 ;
      RECT 0.048 223.488 4.132 223.584 ;
      RECT 0.048 224.256 4.132 224.352 ;
      RECT 0.048 225.024 4.132 225.120 ;
      RECT 0.048 225.792 4.132 225.888 ;
      RECT 0.048 226.560 4.132 226.656 ;
      RECT 0.048 227.328 4.132 227.424 ;
      RECT 0.048 228.096 4.132 228.192 ;
      RECT 0.048 228.864 4.132 228.960 ;
      RECT 0.048 229.632 4.132 229.728 ;
      RECT 0.048 230.400 4.132 230.496 ;
      RECT 0.048 231.168 4.132 231.264 ;
      RECT 0.048 231.936 4.132 232.032 ;
      RECT 0.048 232.704 4.132 232.800 ;
      RECT 0.048 233.472 4.132 233.568 ;
      RECT 0.048 234.240 4.132 234.336 ;
      RECT 0.048 235.008 4.132 235.104 ;
      RECT 0.048 235.776 4.132 235.872 ;
      RECT 0.048 236.544 4.132 236.640 ;
      RECT 0.048 237.312 4.132 237.408 ;
      RECT 0.048 238.080 4.132 238.176 ;
      RECT 0.048 238.848 4.132 238.944 ;
      RECT 0.048 239.616 4.132 239.712 ;
      RECT 0.048 240.384 4.132 240.480 ;
      RECT 0.048 241.152 4.132 241.248 ;
      RECT 0.048 241.920 4.132 242.016 ;
      RECT 0.048 242.688 4.132 242.784 ;
      RECT 0.048 243.456 4.132 243.552 ;
      RECT 0.048 244.224 4.132 244.320 ;
      RECT 0.048 244.992 4.132 245.088 ;
      RECT 0.048 245.760 4.132 245.856 ;
      RECT 0.048 246.528 4.132 246.624 ;
      RECT 0.048 247.296 4.132 247.392 ;
      RECT 0.048 248.064 4.132 248.160 ;
      RECT 0.048 248.832 4.132 248.928 ;
      RECT 0.048 249.600 4.132 249.696 ;
      RECT 0.048 250.368 4.132 250.464 ;
      RECT 0.048 251.136 4.132 251.232 ;
      RECT 0.048 251.904 4.132 252.000 ;
      RECT 0.048 252.672 4.132 252.768 ;
      RECT 0.048 253.440 4.132 253.536 ;
      RECT 0.048 254.208 4.132 254.304 ;
      RECT 0.048 254.976 4.132 255.072 ;
      RECT 0.048 255.744 4.132 255.840 ;
      RECT 0.048 256.512 4.132 256.608 ;
      RECT 0.048 257.280 4.132 257.376 ;
      RECT 0.048 258.048 4.132 258.144 ;
      RECT 0.048 258.816 4.132 258.912 ;
      RECT 0.048 259.584 4.132 259.680 ;
      RECT 0.048 260.352 4.132 260.448 ;
      RECT 0.048 261.120 4.132 261.216 ;
      RECT 0.048 261.888 4.132 261.984 ;
      RECT 0.048 262.656 4.132 262.752 ;
      RECT 0.048 263.424 4.132 263.520 ;
      RECT 0.048 264.192 4.132 264.288 ;
      RECT 0.048 264.960 4.132 265.056 ;
      RECT 0.048 265.728 4.132 265.824 ;
      RECT 0.048 266.496 4.132 266.592 ;
      RECT 0.048 267.264 4.132 267.360 ;
      RECT 0.048 268.032 4.132 268.128 ;
      RECT 0.048 268.800 4.132 268.896 ;
      RECT 0.048 269.568 4.132 269.664 ;
      RECT 0.048 270.336 4.132 270.432 ;
      RECT 0.048 271.104 4.132 271.200 ;
      RECT 0.048 271.872 4.132 271.968 ;
      RECT 0.048 272.640 4.132 272.736 ;
      RECT 0.048 273.408 4.132 273.504 ;
      RECT 0.048 274.176 4.132 274.272 ;
      RECT 0.048 274.944 4.132 275.040 ;
      RECT 0.048 275.712 4.132 275.808 ;
      RECT 0.048 276.480 4.132 276.576 ;
      RECT 0.048 277.248 4.132 277.344 ;
      RECT 0.048 278.016 4.132 278.112 ;
      RECT 0.048 278.784 4.132 278.880 ;
      RECT 0.048 279.552 4.132 279.648 ;
      RECT 0.048 280.320 4.132 280.416 ;
      RECT 0.048 281.088 4.132 281.184 ;
      RECT 0.048 281.856 4.132 281.952 ;
      RECT 0.048 282.624 4.132 282.720 ;
      RECT 0.048 283.392 4.132 283.488 ;
      RECT 0.048 284.160 4.132 284.256 ;
      RECT 0.048 284.928 4.132 285.024 ;
      RECT 0.048 285.696 4.132 285.792 ;
      RECT 0.048 286.464 4.132 286.560 ;
      RECT 0.048 287.232 4.132 287.328 ;
      RECT 0.048 288.000 4.132 288.096 ;
      RECT 0.048 288.768 4.132 288.864 ;
      RECT 0.048 289.536 4.132 289.632 ;
      RECT 0.048 290.304 4.132 290.400 ;
      RECT 0.048 291.072 4.132 291.168 ;
      RECT 0.048 291.840 4.132 291.936 ;
      RECT 0.048 292.608 4.132 292.704 ;
      RECT 0.048 293.376 4.132 293.472 ;
      RECT 0.048 294.144 4.132 294.240 ;
      RECT 0.048 294.912 4.132 295.008 ;
      RECT 0.048 295.680 4.132 295.776 ;
      RECT 0.048 296.448 4.132 296.544 ;
      RECT 0.048 297.216 4.132 297.312 ;
      RECT 0.048 297.984 4.132 298.080 ;
      RECT 0.048 298.752 4.132 298.848 ;
      RECT 0.048 299.520 4.132 299.616 ;
      RECT 0.048 300.288 4.132 300.384 ;
      RECT 0.048 301.056 4.132 301.152 ;
      RECT 0.048 301.824 4.132 301.920 ;
      RECT 0.048 302.592 4.132 302.688 ;
      RECT 0.048 303.360 4.132 303.456 ;
      RECT 0.048 304.128 4.132 304.224 ;
      RECT 0.048 304.896 4.132 304.992 ;
      RECT 0.048 305.664 4.132 305.760 ;
      RECT 0.048 306.432 4.132 306.528 ;
      RECT 0.048 307.200 4.132 307.296 ;
      RECT 0.048 307.968 4.132 308.064 ;
      RECT 0.048 308.736 4.132 308.832 ;
      RECT 0.048 309.504 4.132 309.600 ;
      RECT 0.048 310.272 4.132 310.368 ;
      RECT 0.048 311.040 4.132 311.136 ;
      RECT 0.048 311.808 4.132 311.904 ;
      RECT 0.048 312.576 4.132 312.672 ;
      RECT 0.048 313.344 4.132 313.440 ;
      RECT 0.048 314.112 4.132 314.208 ;
      RECT 0.048 314.880 4.132 314.976 ;
      RECT 0.048 315.648 4.132 315.744 ;
      RECT 0.048 316.416 4.132 316.512 ;
      RECT 0.048 317.184 4.132 317.280 ;
      RECT 0.048 317.952 4.132 318.048 ;
      RECT 0.048 318.720 4.132 318.816 ;
      RECT 0.048 319.488 4.132 319.584 ;
      RECT 0.048 320.256 4.132 320.352 ;
      RECT 0.048 321.024 4.132 321.120 ;
      RECT 0.048 321.792 4.132 321.888 ;
      RECT 0.048 322.560 4.132 322.656 ;
      RECT 0.048 323.328 4.132 323.424 ;
      RECT 0.048 324.096 4.132 324.192 ;
      RECT 0.048 324.864 4.132 324.960 ;
      RECT 0.048 325.632 4.132 325.728 ;
      RECT 0.048 326.400 4.132 326.496 ;
      RECT 0.048 327.168 4.132 327.264 ;
      RECT 0.048 327.936 4.132 328.032 ;
      RECT 0.048 328.704 4.132 328.800 ;
      RECT 0.048 329.472 4.132 329.568 ;
      RECT 0.048 330.240 4.132 330.336 ;
      RECT 0.048 331.008 4.132 331.104 ;
    END
  END VSS
  PIN VDD
    DIRECTION INOUT ;
    USE POWER ;
    PORT
      LAYER M4 ;
      RECT 0.048 0.384 4.132 0.480 ;
      RECT 0.048 1.152 4.132 1.248 ;
      RECT 0.048 1.920 4.132 2.016 ;
      RECT 0.048 2.688 4.132 2.784 ;
      RECT 0.048 3.456 4.132 3.552 ;
      RECT 0.048 4.224 4.132 4.320 ;
      RECT 0.048 4.992 4.132 5.088 ;
      RECT 0.048 5.760 4.132 5.856 ;
      RECT 0.048 6.528 4.132 6.624 ;
      RECT 0.048 7.296 4.132 7.392 ;
      RECT 0.048 8.064 4.132 8.160 ;
      RECT 0.048 8.832 4.132 8.928 ;
      RECT 0.048 9.600 4.132 9.696 ;
      RECT 0.048 10.368 4.132 10.464 ;
      RECT 0.048 11.136 4.132 11.232 ;
      RECT 0.048 11.904 4.132 12.000 ;
      RECT 0.048 12.672 4.132 12.768 ;
      RECT 0.048 13.440 4.132 13.536 ;
      RECT 0.048 14.208 4.132 14.304 ;
      RECT 0.048 14.976 4.132 15.072 ;
      RECT 0.048 15.744 4.132 15.840 ;
      RECT 0.048 16.512 4.132 16.608 ;
      RECT 0.048 17.280 4.132 17.376 ;
      RECT 0.048 18.048 4.132 18.144 ;
      RECT 0.048 18.816 4.132 18.912 ;
      RECT 0.048 19.584 4.132 19.680 ;
      RECT 0.048 20.352 4.132 20.448 ;
      RECT 0.048 21.120 4.132 21.216 ;
      RECT 0.048 21.888 4.132 21.984 ;
      RECT 0.048 22.656 4.132 22.752 ;
      RECT 0.048 23.424 4.132 23.520 ;
      RECT 0.048 24.192 4.132 24.288 ;
      RECT 0.048 24.960 4.132 25.056 ;
      RECT 0.048 25.728 4.132 25.824 ;
      RECT 0.048 26.496 4.132 26.592 ;
      RECT 0.048 27.264 4.132 27.360 ;
      RECT 0.048 28.032 4.132 28.128 ;
      RECT 0.048 28.800 4.132 28.896 ;
      RECT 0.048 29.568 4.132 29.664 ;
      RECT 0.048 30.336 4.132 30.432 ;
      RECT 0.048 31.104 4.132 31.200 ;
      RECT 0.048 31.872 4.132 31.968 ;
      RECT 0.048 32.640 4.132 32.736 ;
      RECT 0.048 33.408 4.132 33.504 ;
      RECT 0.048 34.176 4.132 34.272 ;
      RECT 0.048 34.944 4.132 35.040 ;
      RECT 0.048 35.712 4.132 35.808 ;
      RECT 0.048 36.480 4.132 36.576 ;
      RECT 0.048 37.248 4.132 37.344 ;
      RECT 0.048 38.016 4.132 38.112 ;
      RECT 0.048 38.784 4.132 38.880 ;
      RECT 0.048 39.552 4.132 39.648 ;
      RECT 0.048 40.320 4.132 40.416 ;
      RECT 0.048 41.088 4.132 41.184 ;
      RECT 0.048 41.856 4.132 41.952 ;
      RECT 0.048 42.624 4.132 42.720 ;
      RECT 0.048 43.392 4.132 43.488 ;
      RECT 0.048 44.160 4.132 44.256 ;
      RECT 0.048 44.928 4.132 45.024 ;
      RECT 0.048 45.696 4.132 45.792 ;
      RECT 0.048 46.464 4.132 46.560 ;
      RECT 0.048 47.232 4.132 47.328 ;
      RECT 0.048 48.000 4.132 48.096 ;
      RECT 0.048 48.768 4.132 48.864 ;
      RECT 0.048 49.536 4.132 49.632 ;
      RECT 0.048 50.304 4.132 50.400 ;
      RECT 0.048 51.072 4.132 51.168 ;
      RECT 0.048 51.840 4.132 51.936 ;
      RECT 0.048 52.608 4.132 52.704 ;
      RECT 0.048 53.376 4.132 53.472 ;
      RECT 0.048 54.144 4.132 54.240 ;
      RECT 0.048 54.912 4.132 55.008 ;
      RECT 0.048 55.680 4.132 55.776 ;
      RECT 0.048 56.448 4.132 56.544 ;
      RECT 0.048 57.216 4.132 57.312 ;
      RECT 0.048 57.984 4.132 58.080 ;
      RECT 0.048 58.752 4.132 58.848 ;
      RECT 0.048 59.520 4.132 59.616 ;
      RECT 0.048 60.288 4.132 60.384 ;
      RECT 0.048 61.056 4.132 61.152 ;
      RECT 0.048 61.824 4.132 61.920 ;
      RECT 0.048 62.592 4.132 62.688 ;
      RECT 0.048 63.360 4.132 63.456 ;
      RECT 0.048 64.128 4.132 64.224 ;
      RECT 0.048 64.896 4.132 64.992 ;
      RECT 0.048 65.664 4.132 65.760 ;
      RECT 0.048 66.432 4.132 66.528 ;
      RECT 0.048 67.200 4.132 67.296 ;
      RECT 0.048 67.968 4.132 68.064 ;
      RECT 0.048 68.736 4.132 68.832 ;
      RECT 0.048 69.504 4.132 69.600 ;
      RECT 0.048 70.272 4.132 70.368 ;
      RECT 0.048 71.040 4.132 71.136 ;
      RECT 0.048 71.808 4.132 71.904 ;
      RECT 0.048 72.576 4.132 72.672 ;
      RECT 0.048 73.344 4.132 73.440 ;
      RECT 0.048 74.112 4.132 74.208 ;
      RECT 0.048 74.880 4.132 74.976 ;
      RECT 0.048 75.648 4.132 75.744 ;
      RECT 0.048 76.416 4.132 76.512 ;
      RECT 0.048 77.184 4.132 77.280 ;
      RECT 0.048 77.952 4.132 78.048 ;
      RECT 0.048 78.720 4.132 78.816 ;
      RECT 0.048 79.488 4.132 79.584 ;
      RECT 0.048 80.256 4.132 80.352 ;
      RECT 0.048 81.024 4.132 81.120 ;
      RECT 0.048 81.792 4.132 81.888 ;
      RECT 0.048 82.560 4.132 82.656 ;
      RECT 0.048 83.328 4.132 83.424 ;
      RECT 0.048 84.096 4.132 84.192 ;
      RECT 0.048 84.864 4.132 84.960 ;
      RECT 0.048 85.632 4.132 85.728 ;
      RECT 0.048 86.400 4.132 86.496 ;
      RECT 0.048 87.168 4.132 87.264 ;
      RECT 0.048 87.936 4.132 88.032 ;
      RECT 0.048 88.704 4.132 88.800 ;
      RECT 0.048 89.472 4.132 89.568 ;
      RECT 0.048 90.240 4.132 90.336 ;
      RECT 0.048 91.008 4.132 91.104 ;
      RECT 0.048 91.776 4.132 91.872 ;
      RECT 0.048 92.544 4.132 92.640 ;
      RECT 0.048 93.312 4.132 93.408 ;
      RECT 0.048 94.080 4.132 94.176 ;
      RECT 0.048 94.848 4.132 94.944 ;
      RECT 0.048 95.616 4.132 95.712 ;
      RECT 0.048 96.384 4.132 96.480 ;
      RECT 0.048 97.152 4.132 97.248 ;
      RECT 0.048 97.920 4.132 98.016 ;
      RECT 0.048 98.688 4.132 98.784 ;
      RECT 0.048 99.456 4.132 99.552 ;
      RECT 0.048 100.224 4.132 100.320 ;
      RECT 0.048 100.992 4.132 101.088 ;
      RECT 0.048 101.760 4.132 101.856 ;
      RECT 0.048 102.528 4.132 102.624 ;
      RECT 0.048 103.296 4.132 103.392 ;
      RECT 0.048 104.064 4.132 104.160 ;
      RECT 0.048 104.832 4.132 104.928 ;
      RECT 0.048 105.600 4.132 105.696 ;
      RECT 0.048 106.368 4.132 106.464 ;
      RECT 0.048 107.136 4.132 107.232 ;
      RECT 0.048 107.904 4.132 108.000 ;
      RECT 0.048 108.672 4.132 108.768 ;
      RECT 0.048 109.440 4.132 109.536 ;
      RECT 0.048 110.208 4.132 110.304 ;
      RECT 0.048 110.976 4.132 111.072 ;
      RECT 0.048 111.744 4.132 111.840 ;
      RECT 0.048 112.512 4.132 112.608 ;
      RECT 0.048 113.280 4.132 113.376 ;
      RECT 0.048 114.048 4.132 114.144 ;
      RECT 0.048 114.816 4.132 114.912 ;
      RECT 0.048 115.584 4.132 115.680 ;
      RECT 0.048 116.352 4.132 116.448 ;
      RECT 0.048 117.120 4.132 117.216 ;
      RECT 0.048 117.888 4.132 117.984 ;
      RECT 0.048 118.656 4.132 118.752 ;
      RECT 0.048 119.424 4.132 119.520 ;
      RECT 0.048 120.192 4.132 120.288 ;
      RECT 0.048 120.960 4.132 121.056 ;
      RECT 0.048 121.728 4.132 121.824 ;
      RECT 0.048 122.496 4.132 122.592 ;
      RECT 0.048 123.264 4.132 123.360 ;
      RECT 0.048 124.032 4.132 124.128 ;
      RECT 0.048 124.800 4.132 124.896 ;
      RECT 0.048 125.568 4.132 125.664 ;
      RECT 0.048 126.336 4.132 126.432 ;
      RECT 0.048 127.104 4.132 127.200 ;
      RECT 0.048 127.872 4.132 127.968 ;
      RECT 0.048 128.640 4.132 128.736 ;
      RECT 0.048 129.408 4.132 129.504 ;
      RECT 0.048 130.176 4.132 130.272 ;
      RECT 0.048 130.944 4.132 131.040 ;
      RECT 0.048 131.712 4.132 131.808 ;
      RECT 0.048 132.480 4.132 132.576 ;
      RECT 0.048 133.248 4.132 133.344 ;
      RECT 0.048 134.016 4.132 134.112 ;
      RECT 0.048 134.784 4.132 134.880 ;
      RECT 0.048 135.552 4.132 135.648 ;
      RECT 0.048 136.320 4.132 136.416 ;
      RECT 0.048 137.088 4.132 137.184 ;
      RECT 0.048 137.856 4.132 137.952 ;
      RECT 0.048 138.624 4.132 138.720 ;
      RECT 0.048 139.392 4.132 139.488 ;
      RECT 0.048 140.160 4.132 140.256 ;
      RECT 0.048 140.928 4.132 141.024 ;
      RECT 0.048 141.696 4.132 141.792 ;
      RECT 0.048 142.464 4.132 142.560 ;
      RECT 0.048 143.232 4.132 143.328 ;
      RECT 0.048 144.000 4.132 144.096 ;
      RECT 0.048 144.768 4.132 144.864 ;
      RECT 0.048 145.536 4.132 145.632 ;
      RECT 0.048 146.304 4.132 146.400 ;
      RECT 0.048 147.072 4.132 147.168 ;
      RECT 0.048 147.840 4.132 147.936 ;
      RECT 0.048 148.608 4.132 148.704 ;
      RECT 0.048 149.376 4.132 149.472 ;
      RECT 0.048 150.144 4.132 150.240 ;
      RECT 0.048 150.912 4.132 151.008 ;
      RECT 0.048 151.680 4.132 151.776 ;
      RECT 0.048 152.448 4.132 152.544 ;
      RECT 0.048 153.216 4.132 153.312 ;
      RECT 0.048 153.984 4.132 154.080 ;
      RECT 0.048 154.752 4.132 154.848 ;
      RECT 0.048 155.520 4.132 155.616 ;
      RECT 0.048 156.288 4.132 156.384 ;
      RECT 0.048 157.056 4.132 157.152 ;
      RECT 0.048 157.824 4.132 157.920 ;
      RECT 0.048 158.592 4.132 158.688 ;
      RECT 0.048 159.360 4.132 159.456 ;
      RECT 0.048 160.128 4.132 160.224 ;
      RECT 0.048 160.896 4.132 160.992 ;
      RECT 0.048 161.664 4.132 161.760 ;
      RECT 0.048 162.432 4.132 162.528 ;
      RECT 0.048 163.200 4.132 163.296 ;
      RECT 0.048 163.968 4.132 164.064 ;
      RECT 0.048 164.736 4.132 164.832 ;
      RECT 0.048 165.504 4.132 165.600 ;
      RECT 0.048 166.272 4.132 166.368 ;
      RECT 0.048 167.040 4.132 167.136 ;
      RECT 0.048 167.808 4.132 167.904 ;
      RECT 0.048 168.576 4.132 168.672 ;
      RECT 0.048 169.344 4.132 169.440 ;
      RECT 0.048 170.112 4.132 170.208 ;
      RECT 0.048 170.880 4.132 170.976 ;
      RECT 0.048 171.648 4.132 171.744 ;
      RECT 0.048 172.416 4.132 172.512 ;
      RECT 0.048 173.184 4.132 173.280 ;
      RECT 0.048 173.952 4.132 174.048 ;
      RECT 0.048 174.720 4.132 174.816 ;
      RECT 0.048 175.488 4.132 175.584 ;
      RECT 0.048 176.256 4.132 176.352 ;
      RECT 0.048 177.024 4.132 177.120 ;
      RECT 0.048 177.792 4.132 177.888 ;
      RECT 0.048 178.560 4.132 178.656 ;
      RECT 0.048 179.328 4.132 179.424 ;
      RECT 0.048 180.096 4.132 180.192 ;
      RECT 0.048 180.864 4.132 180.960 ;
      RECT 0.048 181.632 4.132 181.728 ;
      RECT 0.048 182.400 4.132 182.496 ;
      RECT 0.048 183.168 4.132 183.264 ;
      RECT 0.048 183.936 4.132 184.032 ;
      RECT 0.048 184.704 4.132 184.800 ;
      RECT 0.048 185.472 4.132 185.568 ;
      RECT 0.048 186.240 4.132 186.336 ;
      RECT 0.048 187.008 4.132 187.104 ;
      RECT 0.048 187.776 4.132 187.872 ;
      RECT 0.048 188.544 4.132 188.640 ;
      RECT 0.048 189.312 4.132 189.408 ;
      RECT 0.048 190.080 4.132 190.176 ;
      RECT 0.048 190.848 4.132 190.944 ;
      RECT 0.048 191.616 4.132 191.712 ;
      RECT 0.048 192.384 4.132 192.480 ;
      RECT 0.048 193.152 4.132 193.248 ;
      RECT 0.048 193.920 4.132 194.016 ;
      RECT 0.048 194.688 4.132 194.784 ;
      RECT 0.048 195.456 4.132 195.552 ;
      RECT 0.048 196.224 4.132 196.320 ;
      RECT 0.048 196.992 4.132 197.088 ;
      RECT 0.048 197.760 4.132 197.856 ;
      RECT 0.048 198.528 4.132 198.624 ;
      RECT 0.048 199.296 4.132 199.392 ;
      RECT 0.048 200.064 4.132 200.160 ;
      RECT 0.048 200.832 4.132 200.928 ;
      RECT 0.048 201.600 4.132 201.696 ;
      RECT 0.048 202.368 4.132 202.464 ;
      RECT 0.048 203.136 4.132 203.232 ;
      RECT 0.048 203.904 4.132 204.000 ;
      RECT 0.048 204.672 4.132 204.768 ;
      RECT 0.048 205.440 4.132 205.536 ;
      RECT 0.048 206.208 4.132 206.304 ;
      RECT 0.048 206.976 4.132 207.072 ;
      RECT 0.048 207.744 4.132 207.840 ;
      RECT 0.048 208.512 4.132 208.608 ;
      RECT 0.048 209.280 4.132 209.376 ;
      RECT 0.048 210.048 4.132 210.144 ;
      RECT 0.048 210.816 4.132 210.912 ;
      RECT 0.048 211.584 4.132 211.680 ;
      RECT 0.048 212.352 4.132 212.448 ;
      RECT 0.048 213.120 4.132 213.216 ;
      RECT 0.048 213.888 4.132 213.984 ;
      RECT 0.048 214.656 4.132 214.752 ;
      RECT 0.048 215.424 4.132 215.520 ;
      RECT 0.048 216.192 4.132 216.288 ;
      RECT 0.048 216.960 4.132 217.056 ;
      RECT 0.048 217.728 4.132 217.824 ;
      RECT 0.048 218.496 4.132 218.592 ;
      RECT 0.048 219.264 4.132 219.360 ;
      RECT 0.048 220.032 4.132 220.128 ;
      RECT 0.048 220.800 4.132 220.896 ;
      RECT 0.048 221.568 4.132 221.664 ;
      RECT 0.048 222.336 4.132 222.432 ;
      RECT 0.048 223.104 4.132 223.200 ;
      RECT 0.048 223.872 4.132 223.968 ;
      RECT 0.048 224.640 4.132 224.736 ;
      RECT 0.048 225.408 4.132 225.504 ;
      RECT 0.048 226.176 4.132 226.272 ;
      RECT 0.048 226.944 4.132 227.040 ;
      RECT 0.048 227.712 4.132 227.808 ;
      RECT 0.048 228.480 4.132 228.576 ;
      RECT 0.048 229.248 4.132 229.344 ;
      RECT 0.048 230.016 4.132 230.112 ;
      RECT 0.048 230.784 4.132 230.880 ;
      RECT 0.048 231.552 4.132 231.648 ;
      RECT 0.048 232.320 4.132 232.416 ;
      RECT 0.048 233.088 4.132 233.184 ;
      RECT 0.048 233.856 4.132 233.952 ;
      RECT 0.048 234.624 4.132 234.720 ;
      RECT 0.048 235.392 4.132 235.488 ;
      RECT 0.048 236.160 4.132 236.256 ;
      RECT 0.048 236.928 4.132 237.024 ;
      RECT 0.048 237.696 4.132 237.792 ;
      RECT 0.048 238.464 4.132 238.560 ;
      RECT 0.048 239.232 4.132 239.328 ;
      RECT 0.048 240.000 4.132 240.096 ;
      RECT 0.048 240.768 4.132 240.864 ;
      RECT 0.048 241.536 4.132 241.632 ;
      RECT 0.048 242.304 4.132 242.400 ;
      RECT 0.048 243.072 4.132 243.168 ;
      RECT 0.048 243.840 4.132 243.936 ;
      RECT 0.048 244.608 4.132 244.704 ;
      RECT 0.048 245.376 4.132 245.472 ;
      RECT 0.048 246.144 4.132 246.240 ;
      RECT 0.048 246.912 4.132 247.008 ;
      RECT 0.048 247.680 4.132 247.776 ;
      RECT 0.048 248.448 4.132 248.544 ;
      RECT 0.048 249.216 4.132 249.312 ;
      RECT 0.048 249.984 4.132 250.080 ;
      RECT 0.048 250.752 4.132 250.848 ;
      RECT 0.048 251.520 4.132 251.616 ;
      RECT 0.048 252.288 4.132 252.384 ;
      RECT 0.048 253.056 4.132 253.152 ;
      RECT 0.048 253.824 4.132 253.920 ;
      RECT 0.048 254.592 4.132 254.688 ;
      RECT 0.048 255.360 4.132 255.456 ;
      RECT 0.048 256.128 4.132 256.224 ;
      RECT 0.048 256.896 4.132 256.992 ;
      RECT 0.048 257.664 4.132 257.760 ;
      RECT 0.048 258.432 4.132 258.528 ;
      RECT 0.048 259.200 4.132 259.296 ;
      RECT 0.048 259.968 4.132 260.064 ;
      RECT 0.048 260.736 4.132 260.832 ;
      RECT 0.048 261.504 4.132 261.600 ;
      RECT 0.048 262.272 4.132 262.368 ;
      RECT 0.048 263.040 4.132 263.136 ;
      RECT 0.048 263.808 4.132 263.904 ;
      RECT 0.048 264.576 4.132 264.672 ;
      RECT 0.048 265.344 4.132 265.440 ;
      RECT 0.048 266.112 4.132 266.208 ;
      RECT 0.048 266.880 4.132 266.976 ;
      RECT 0.048 267.648 4.132 267.744 ;
      RECT 0.048 268.416 4.132 268.512 ;
      RECT 0.048 269.184 4.132 269.280 ;
      RECT 0.048 269.952 4.132 270.048 ;
      RECT 0.048 270.720 4.132 270.816 ;
      RECT 0.048 271.488 4.132 271.584 ;
      RECT 0.048 272.256 4.132 272.352 ;
      RECT 0.048 273.024 4.132 273.120 ;
      RECT 0.048 273.792 4.132 273.888 ;
      RECT 0.048 274.560 4.132 274.656 ;
      RECT 0.048 275.328 4.132 275.424 ;
      RECT 0.048 276.096 4.132 276.192 ;
      RECT 0.048 276.864 4.132 276.960 ;
      RECT 0.048 277.632 4.132 277.728 ;
      RECT 0.048 278.400 4.132 278.496 ;
      RECT 0.048 279.168 4.132 279.264 ;
      RECT 0.048 279.936 4.132 280.032 ;
      RECT 0.048 280.704 4.132 280.800 ;
      RECT 0.048 281.472 4.132 281.568 ;
      RECT 0.048 282.240 4.132 282.336 ;
      RECT 0.048 283.008 4.132 283.104 ;
      RECT 0.048 283.776 4.132 283.872 ;
      RECT 0.048 284.544 4.132 284.640 ;
      RECT 0.048 285.312 4.132 285.408 ;
      RECT 0.048 286.080 4.132 286.176 ;
      RECT 0.048 286.848 4.132 286.944 ;
      RECT 0.048 287.616 4.132 287.712 ;
      RECT 0.048 288.384 4.132 288.480 ;
      RECT 0.048 289.152 4.132 289.248 ;
      RECT 0.048 289.920 4.132 290.016 ;
      RECT 0.048 290.688 4.132 290.784 ;
      RECT 0.048 291.456 4.132 291.552 ;
      RECT 0.048 292.224 4.132 292.320 ;
      RECT 0.048 292.992 4.132 293.088 ;
      RECT 0.048 293.760 4.132 293.856 ;
      RECT 0.048 294.528 4.132 294.624 ;
      RECT 0.048 295.296 4.132 295.392 ;
      RECT 0.048 296.064 4.132 296.160 ;
      RECT 0.048 296.832 4.132 296.928 ;
      RECT 0.048 297.600 4.132 297.696 ;
      RECT 0.048 298.368 4.132 298.464 ;
      RECT 0.048 299.136 4.132 299.232 ;
      RECT 0.048 299.904 4.132 300.000 ;
      RECT 0.048 300.672 4.132 300.768 ;
      RECT 0.048 301.440 4.132 301.536 ;
      RECT 0.048 302.208 4.132 302.304 ;
      RECT 0.048 302.976 4.132 303.072 ;
      RECT 0.048 303.744 4.132 303.840 ;
      RECT 0.048 304.512 4.132 304.608 ;
      RECT 0.048 305.280 4.132 305.376 ;
      RECT 0.048 306.048 4.132 306.144 ;
      RECT 0.048 306.816 4.132 306.912 ;
      RECT 0.048 307.584 4.132 307.680 ;
      RECT 0.048 308.352 4.132 308.448 ;
      RECT 0.048 309.120 4.132 309.216 ;
      RECT 0.048 309.888 4.132 309.984 ;
      RECT 0.048 310.656 4.132 310.752 ;
      RECT 0.048 311.424 4.132 311.520 ;
      RECT 0.048 312.192 4.132 312.288 ;
      RECT 0.048 312.960 4.132 313.056 ;
      RECT 0.048 313.728 4.132 313.824 ;
      RECT 0.048 314.496 4.132 314.592 ;
      RECT 0.048 315.264 4.132 315.360 ;
      RECT 0.048 316.032 4.132 316.128 ;
      RECT 0.048 316.800 4.132 316.896 ;
      RECT 0.048 317.568 4.132 317.664 ;
      RECT 0.048 318.336 4.132 318.432 ;
      RECT 0.048 319.104 4.132 319.200 ;
      RECT 0.048 319.872 4.132 319.968 ;
      RECT 0.048 320.640 4.132 320.736 ;
      RECT 0.048 321.408 4.132 321.504 ;
      RECT 0.048 322.176 4.132 322.272 ;
      RECT 0.048 322.944 4.132 323.040 ;
      RECT 0.048 323.712 4.132 323.808 ;
      RECT 0.048 324.480 4.132 324.576 ;
      RECT 0.048 325.248 4.132 325.344 ;
      RECT 0.048 326.016 4.132 326.112 ;
      RECT 0.048 326.784 4.132 326.880 ;
      RECT 0.048 327.552 4.132 327.648 ;
      RECT 0.048 328.320 4.132 328.416 ;
      RECT 0.048 329.088 4.132 329.184 ;
      RECT 0.048 329.856 4.132 329.952 ;
      RECT 0.048 330.624 4.132 330.720 ;
      RECT 0.048 331.392 4.132 331.488 ;
    END
  END VDD
  OBS
    LAYER M1 ;
    RECT 0 0 4.180 331.800 ;
    LAYER M2 ;
    RECT 0 0 4.180 331.800 ;
    LAYER M3 ;
    RECT 0 0 4.180 331.800 ;
  END
END fakeram_32x1024
END LIBRARY
